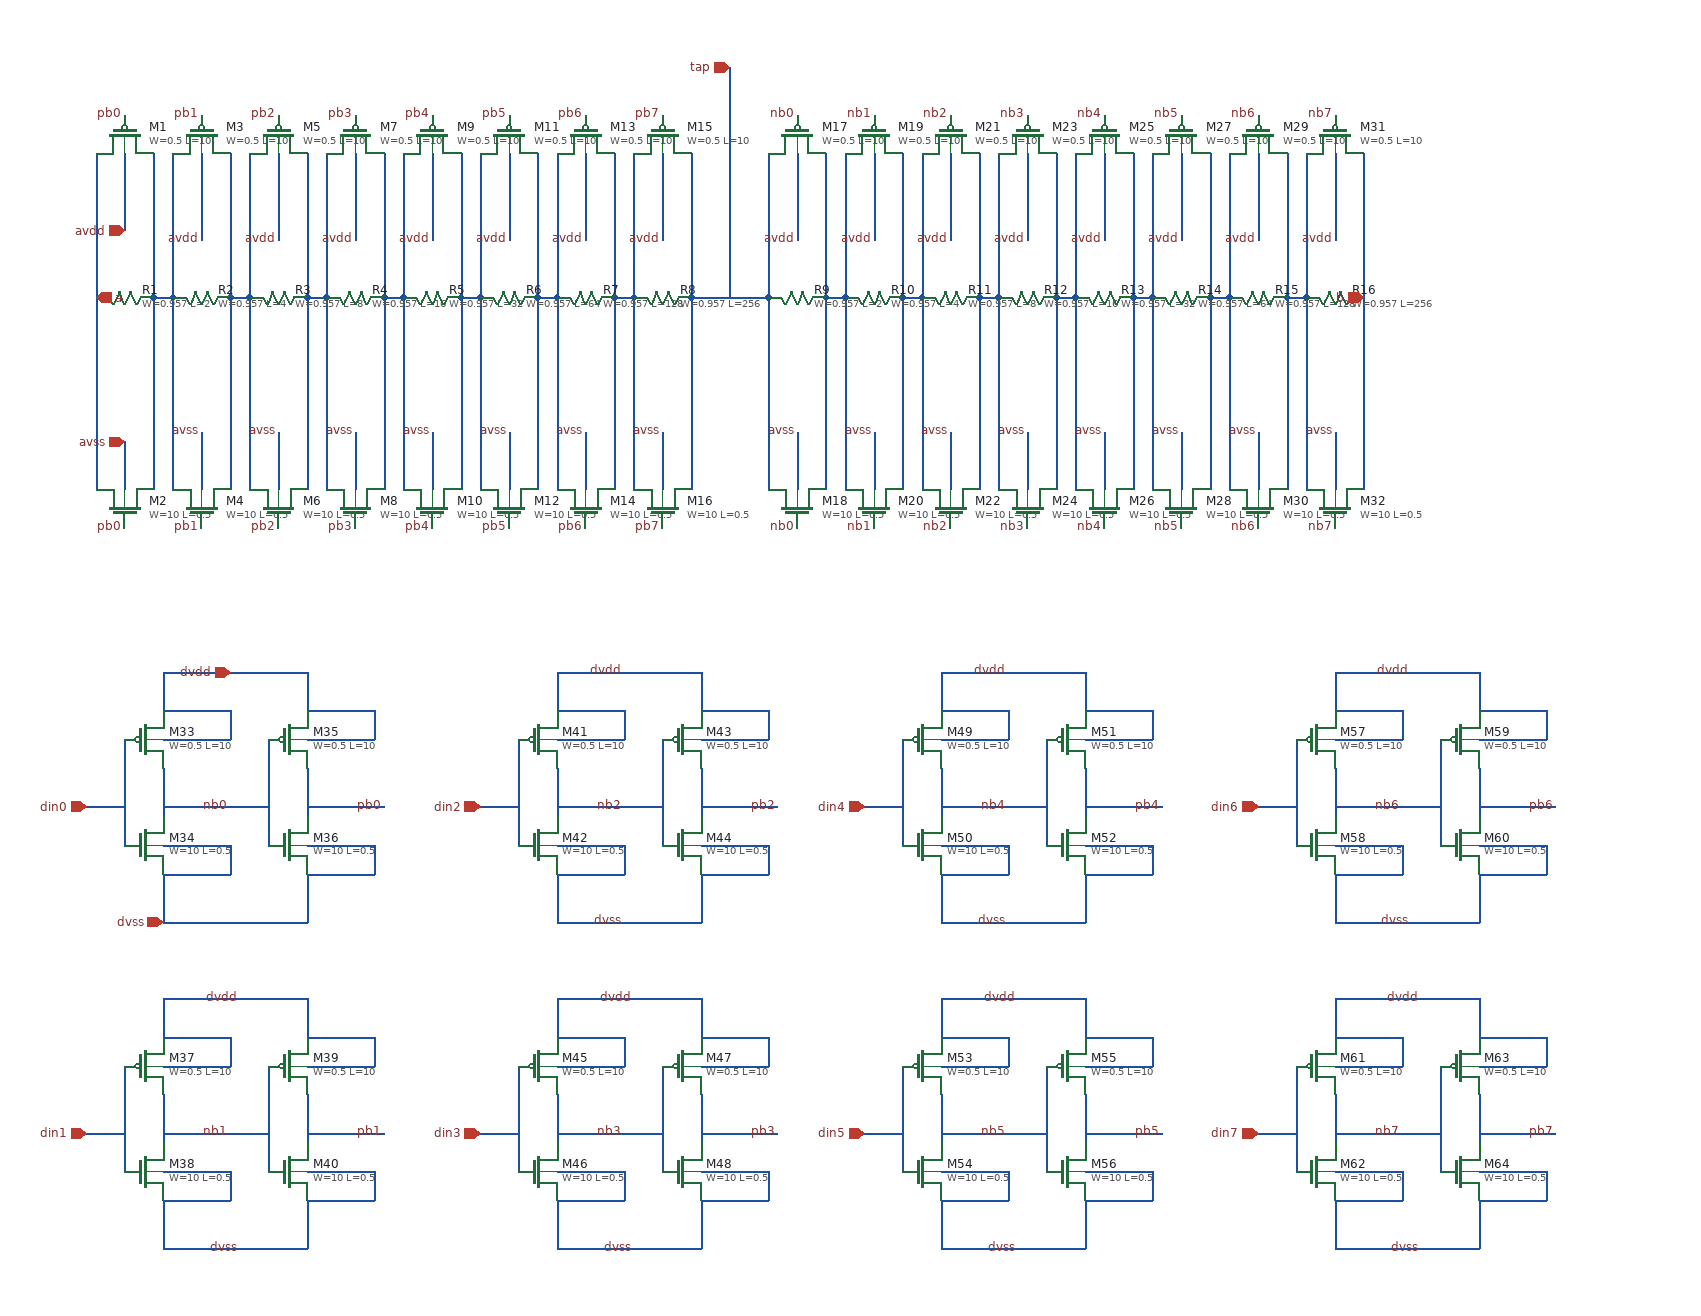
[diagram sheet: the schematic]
v {xschem version=3.4.5 file_version=1.2
}
G {}
K {}
V {}
S {}
E {}
N 70 -1160 70 -990 {
lab=a}
N 130 -1160 130 -990 {
lab=#net1}
N 150 -1160 150 -990 {
lab=#net1}
N 210 -1160 210 -990 {
lab=#net2}
N 230 -1160 230 -990 {
lab=#net2}
N 290 -1160 290 -990 {
lab=#net3}
N 310 -1160 310 -990 {
lab=#net3}
N 370 -1160 370 -990 {
lab=#net4}
N 390 -1160 390 -990 {
lab=#net4}
N 450 -1160 450 -990 {
lab=#net5}
N 470 -1160 470 -990 {
lab=#net5}
N 530 -1160 530 -990 {
lab=#net6}
N 550 -1160 550 -990 {
lab=#net6}
N 610 -1160 610 -990 {
lab=#net7}
N 630 -1160 630 -990 {
lab=#net7}
N 690 -1160 690 -990 {
lab=tap}
N 70 -990 70 -960 {
lab=a}
N 130 -990 130 -960 {
lab=#net1}
N 150 -990 150 -960 {
lab=#net1}
N 210 -990 210 -960 {
lab=#net2}
N 230 -990 230 -960 {
lab=#net2}
N 290 -990 290 -960 {
lab=#net3}
N 310 -990 310 -960 {
lab=#net3}
N 370 -990 370 -960 {
lab=#net4}
N 390 -990 390 -960 {
lab=#net4}
N 450 -990 450 -960 {
lab=#net5}
N 470 -990 470 -960 {
lab=#net5}
N 530 -990 530 -960 {
lab=#net6}
N 550 -990 550 -960 {
lab=#net6}
N 610 -990 610 -960 {
lab=#net7}
N 630 -990 630 -960 {
lab=#net7}
N 690 -990 690 -960 {
lab=tap}
N 70 -1310 70 -1160 {
lab=a}
N 130 -1310 130 -1160 {
lab=#net1}
N 150 -1310 150 -1160 {
lab=#net1}
N 210 -1310 210 -1160 {
lab=#net2}
N 230 -1310 230 -1160 {
lab=#net2}
N 290 -1310 290 -1160 {
lab=#net3}
N 310 -1310 310 -1160 {
lab=#net3}
N 370 -1310 370 -1160 {
lab=#net4}
N 390 -1310 390 -1160 {
lab=#net4}
N 450 -1310 450 -1160 {
lab=#net5}
N 470 -1310 470 -1160 {
lab=#net5}
N 530 -1310 530 -1160 {
lab=#net6}
N 550 -1310 550 -1160 {
lab=#net6}
N 610 -1310 610 -1160 {
lab=#net7}
N 630 -1310 630 -1160 {
lab=#net7}
N 690 -1310 690 -1160 {
lab=tap}
N 130 -1160 150 -1160 {
lab=#net1}
N 210 -1160 230 -1160 {
lab=#net2}
N 290 -1160 310 -1160 {
lab=#net3}
N 370 -1160 390 -1160 {
lab=#net4}
N 450 -1160 470 -1160 {
lab=#net5}
N 530 -1160 550 -1160 {
lab=#net6}
N 610 -1160 630 -1160 {
lab=#net7}
N 690 -1160 770 -1160 {
lab=tap}
N 770 -1160 770 -990 {
lab=tap}
N 830 -1160 830 -990 {
lab=#net8}
N 850 -1160 850 -990 {
lab=#net8}
N 910 -1160 910 -990 {
lab=#net9}
N 930 -1160 930 -990 {
lab=#net9}
N 990 -1160 990 -990 {
lab=#net10}
N 1010 -1160 1010 -990 {
lab=#net10}
N 1070 -1160 1070 -990 {
lab=#net11}
N 1090 -1160 1090 -990 {
lab=#net11}
N 1150 -1160 1150 -990 {
lab=#net12}
N 1170 -1160 1170 -990 {
lab=#net12}
N 1230 -1160 1230 -990 {
lab=#net13}
N 1250 -1160 1250 -990 {
lab=#net13}
N 1310 -1160 1310 -990 {
lab=#net14}
N 1330 -1160 1330 -990 {
lab=#net14}
N 1390 -1160 1390 -990 {
lab=b}
N 770 -990 770 -960 {
lab=tap}
N 830 -990 830 -960 {
lab=#net8}
N 850 -990 850 -960 {
lab=#net8}
N 910 -990 910 -960 {
lab=#net9}
N 930 -990 930 -960 {
lab=#net9}
N 990 -990 990 -960 {
lab=#net10}
N 1010 -990 1010 -960 {
lab=#net10}
N 1070 -990 1070 -960 {
lab=#net11}
N 1090 -990 1090 -960 {
lab=#net11}
N 1150 -990 1150 -960 {
lab=#net12}
N 1170 -990 1170 -960 {
lab=#net12}
N 1230 -990 1230 -960 {
lab=#net13}
N 1250 -990 1250 -960 {
lab=#net13}
N 1310 -990 1310 -960 {
lab=#net14}
N 1330 -990 1330 -960 {
lab=#net14}
N 1390 -990 1390 -960 {
lab=b}
N 770 -1310 770 -1160 {
lab=tap}
N 830 -1310 830 -1160 {
lab=#net8}
N 850 -1310 850 -1160 {
lab=#net8}
N 910 -1310 910 -1160 {
lab=#net9}
N 930 -1310 930 -1160 {
lab=#net9}
N 990 -1310 990 -1160 {
lab=#net10}
N 1010 -1310 1010 -1160 {
lab=#net10}
N 1070 -1310 1070 -1160 {
lab=#net11}
N 1090 -1310 1090 -1160 {
lab=#net11}
N 1150 -1310 1150 -1160 {
lab=#net12}
N 1170 -1310 1170 -1160 {
lab=#net12}
N 1230 -1310 1230 -1160 {
lab=#net13}
N 1250 -1310 1250 -1160 {
lab=#net13}
N 1310 -1310 1310 -1160 {
lab=#net14}
N 1330 -1310 1330 -1160 {
lab=#net14}
N 1390 -1310 1390 -1160 {
lab=b}
N 830 -1160 850 -1160 {
lab=#net8}
N 910 -1160 930 -1160 {
lab=#net9}
N 990 -1160 1010 -1160 {
lab=#net10}
N 1070 -1160 1090 -1160 {
lab=#net11}
N 1150 -1160 1170 -1160 {
lab=#net12}
N 1230 -1160 1250 -1160 {
lab=#net13}
N 1310 -1160 1330 -1160 {
lab=#net14}
N 140 -670 140 -620 {
lab=nb0}
N 140 -770 140 -730 {
lab=dvdd}
N 140 -560 140 -510 {
lab=dvss}
N 140 -700 210 -700 {
lab=dvdd}
N 210 -730 210 -700 {
lab=dvdd}
N 140 -730 210 -730 {
lab=dvdd}
N 140 -590 210 -590 {
lab=dvss}
N 210 -590 210 -560 {
lab=dvss}
N 140 -560 210 -560 {
lab=dvss}
N 100 -670 100 -590 {
lab=din0}
N 100 -700 100 -670 {
lab=din0}
N 290 -670 290 -620 {
lab=pb0}
N 290 -770 290 -730 {
lab=dvdd}
N 290 -560 290 -510 {
lab=dvss}
N 290 -700 360 -700 {
lab=dvdd}
N 360 -730 360 -700 {
lab=dvdd}
N 290 -730 360 -730 {
lab=dvdd}
N 290 -590 360 -590 {
lab=dvss}
N 360 -590 360 -560 {
lab=dvss}
N 290 -560 360 -560 {
lab=dvss}
N 250 -670 250 -590 {
lab=nb0}
N 250 -700 250 -670 {
lab=nb0}
N 140 -630 250 -630 {
lab=nb0}
N 140 -770 290 -770 {
lab=dvdd}
N 140 -510 290 -510 {
lab=dvss}
N 290 -630 370 -630 {
lab=pb0}
N 730 -1400 730 -1160 {
lab=tap}
N 60 -630 100 -630 {
lab=din0}
N 140 -330 140 -280 {
lab=nb1}
N 140 -430 140 -390 {
lab=#net15}
N 140 -220 140 -170 {
lab=#net16}
N 140 -360 210 -360 {
lab=#net15}
N 210 -390 210 -360 {
lab=#net15}
N 140 -390 210 -390 {
lab=#net15}
N 140 -250 210 -250 {
lab=#net16}
N 210 -250 210 -220 {
lab=#net16}
N 140 -220 210 -220 {
lab=#net16}
N 100 -330 100 -250 {
lab=din1}
N 100 -360 100 -330 {
lab=din1}
N 290 -330 290 -280 {
lab=pb1}
N 290 -430 290 -390 {
lab=#net15}
N 290 -220 290 -170 {
lab=#net16}
N 290 -360 360 -360 {
lab=#net15}
N 360 -390 360 -360 {
lab=#net15}
N 290 -390 360 -390 {
lab=#net15}
N 290 -250 360 -250 {
lab=#net16}
N 360 -250 360 -220 {
lab=#net16}
N 290 -220 360 -220 {
lab=#net16}
N 250 -330 250 -250 {
lab=nb1}
N 250 -360 250 -330 {
lab=nb1}
N 140 -290 250 -290 {
lab=nb1}
N 140 -430 290 -430 {
lab=#net15}
N 140 -170 290 -170 {
lab=#net16}
N 290 -290 370 -290 {
lab=pb1}
N 60 -290 100 -290 {
lab=din1}
N 550 -670 550 -620 {
lab=nb2}
N 550 -770 550 -730 {
lab=#net17}
N 550 -560 550 -510 {
lab=#net18}
N 550 -700 620 -700 {
lab=#net17}
N 620 -730 620 -700 {
lab=#net17}
N 550 -730 620 -730 {
lab=#net17}
N 550 -590 620 -590 {
lab=#net18}
N 620 -590 620 -560 {
lab=#net18}
N 550 -560 620 -560 {
lab=#net18}
N 510 -670 510 -590 {
lab=din2}
N 510 -700 510 -670 {
lab=din2}
N 700 -670 700 -620 {
lab=pb2}
N 700 -770 700 -730 {
lab=#net17}
N 700 -560 700 -510 {
lab=#net18}
N 700 -700 770 -700 {
lab=#net17}
N 770 -730 770 -700 {
lab=#net17}
N 700 -730 770 -730 {
lab=#net17}
N 700 -590 770 -590 {
lab=#net18}
N 770 -590 770 -560 {
lab=#net18}
N 700 -560 770 -560 {
lab=#net18}
N 660 -670 660 -590 {
lab=nb2}
N 660 -700 660 -670 {
lab=nb2}
N 550 -630 660 -630 {
lab=nb2}
N 550 -770 700 -770 {
lab=#net17}
N 550 -510 700 -510 {
lab=#net18}
N 700 -630 780 -630 {
lab=pb2}
N 470 -630 510 -630 {
lab=din2}
N 550 -330 550 -280 {
lab=nb3}
N 550 -430 550 -390 {
lab=#net19}
N 550 -220 550 -170 {
lab=#net20}
N 550 -360 620 -360 {
lab=#net19}
N 620 -390 620 -360 {
lab=#net19}
N 550 -390 620 -390 {
lab=#net19}
N 550 -250 620 -250 {
lab=#net20}
N 620 -250 620 -220 {
lab=#net20}
N 550 -220 620 -220 {
lab=#net20}
N 510 -330 510 -250 {
lab=din3}
N 510 -360 510 -330 {
lab=din3}
N 700 -330 700 -280 {
lab=pb3}
N 700 -430 700 -390 {
lab=#net19}
N 700 -220 700 -170 {
lab=#net20}
N 700 -360 770 -360 {
lab=#net19}
N 770 -390 770 -360 {
lab=#net19}
N 700 -390 770 -390 {
lab=#net19}
N 700 -250 770 -250 {
lab=#net20}
N 770 -250 770 -220 {
lab=#net20}
N 700 -220 770 -220 {
lab=#net20}
N 660 -330 660 -250 {
lab=nb3}
N 660 -360 660 -330 {
lab=nb3}
N 550 -290 660 -290 {
lab=nb3}
N 550 -430 700 -430 {
lab=#net19}
N 550 -170 700 -170 {
lab=#net20}
N 700 -290 780 -290 {
lab=pb3}
N 470 -290 510 -290 {
lab=din3}
N 950 -670 950 -620 {
lab=nb4}
N 950 -770 950 -730 {
lab=#net21}
N 950 -560 950 -510 {
lab=#net22}
N 950 -700 1020 -700 {
lab=#net21}
N 1020 -730 1020 -700 {
lab=#net21}
N 950 -730 1020 -730 {
lab=#net21}
N 950 -590 1020 -590 {
lab=#net22}
N 1020 -590 1020 -560 {
lab=#net22}
N 950 -560 1020 -560 {
lab=#net22}
N 910 -670 910 -590 {
lab=din4}
N 910 -700 910 -670 {
lab=din4}
N 1100 -670 1100 -620 {
lab=pb4}
N 1100 -770 1100 -730 {
lab=#net21}
N 1100 -560 1100 -510 {
lab=#net22}
N 1100 -700 1170 -700 {
lab=#net21}
N 1170 -730 1170 -700 {
lab=#net21}
N 1100 -730 1170 -730 {
lab=#net21}
N 1100 -590 1170 -590 {
lab=#net22}
N 1170 -590 1170 -560 {
lab=#net22}
N 1100 -560 1170 -560 {
lab=#net22}
N 1060 -670 1060 -590 {
lab=nb4}
N 1060 -700 1060 -670 {
lab=nb4}
N 950 -630 1060 -630 {
lab=nb4}
N 950 -770 1100 -770 {
lab=#net21}
N 950 -510 1100 -510 {
lab=#net22}
N 1100 -630 1180 -630 {
lab=pb4}
N 870 -630 910 -630 {
lab=din4}
N 950 -330 950 -280 {
lab=nb5}
N 950 -430 950 -390 {
lab=#net23}
N 950 -220 950 -170 {
lab=#net24}
N 950 -360 1020 -360 {
lab=#net23}
N 1020 -390 1020 -360 {
lab=#net23}
N 950 -390 1020 -390 {
lab=#net23}
N 950 -250 1020 -250 {
lab=#net24}
N 1020 -250 1020 -220 {
lab=#net24}
N 950 -220 1020 -220 {
lab=#net24}
N 910 -330 910 -250 {
lab=din5}
N 910 -360 910 -330 {
lab=din5}
N 1100 -330 1100 -280 {
lab=pb5}
N 1100 -430 1100 -390 {
lab=#net23}
N 1100 -220 1100 -170 {
lab=#net24}
N 1100 -360 1170 -360 {
lab=#net23}
N 1170 -390 1170 -360 {
lab=#net23}
N 1100 -390 1170 -390 {
lab=#net23}
N 1100 -250 1170 -250 {
lab=#net24}
N 1170 -250 1170 -220 {
lab=#net24}
N 1100 -220 1170 -220 {
lab=#net24}
N 1060 -330 1060 -250 {
lab=nb5}
N 1060 -360 1060 -330 {
lab=nb5}
N 950 -290 1060 -290 {
lab=nb5}
N 950 -430 1100 -430 {
lab=#net23}
N 950 -170 1100 -170 {
lab=#net24}
N 1100 -290 1180 -290 {
lab=pb5}
N 870 -290 910 -290 {
lab=din5}
N 1360 -670 1360 -620 {
lab=nb6}
N 1360 -770 1360 -730 {
lab=#net25}
N 1360 -560 1360 -510 {
lab=#net26}
N 1360 -700 1430 -700 {
lab=#net25}
N 1430 -730 1430 -700 {
lab=#net25}
N 1360 -730 1430 -730 {
lab=#net25}
N 1360 -590 1430 -590 {
lab=#net26}
N 1430 -590 1430 -560 {
lab=#net26}
N 1360 -560 1430 -560 {
lab=#net26}
N 1320 -670 1320 -590 {
lab=din6}
N 1320 -700 1320 -670 {
lab=din6}
N 1510 -670 1510 -620 {
lab=pb6}
N 1510 -770 1510 -730 {
lab=#net25}
N 1510 -560 1510 -510 {
lab=#net26}
N 1510 -700 1580 -700 {
lab=#net25}
N 1580 -730 1580 -700 {
lab=#net25}
N 1510 -730 1580 -730 {
lab=#net25}
N 1510 -590 1580 -590 {
lab=#net26}
N 1580 -590 1580 -560 {
lab=#net26}
N 1510 -560 1580 -560 {
lab=#net26}
N 1470 -670 1470 -590 {
lab=nb6}
N 1470 -700 1470 -670 {
lab=nb6}
N 1360 -630 1470 -630 {
lab=nb6}
N 1360 -770 1510 -770 {
lab=#net25}
N 1360 -510 1510 -510 {
lab=#net26}
N 1510 -630 1590 -630 {
lab=pb6}
N 1280 -630 1320 -630 {
lab=din6}
N 1360 -330 1360 -280 {
lab=nb7}
N 1360 -430 1360 -390 {
lab=#net27}
N 1360 -220 1360 -170 {
lab=#net28}
N 1360 -360 1430 -360 {
lab=#net27}
N 1430 -390 1430 -360 {
lab=#net27}
N 1360 -390 1430 -390 {
lab=#net27}
N 1360 -250 1430 -250 {
lab=#net28}
N 1430 -250 1430 -220 {
lab=#net28}
N 1360 -220 1430 -220 {
lab=#net28}
N 1320 -330 1320 -250 {
lab=din7}
N 1320 -360 1320 -330 {
lab=din7}
N 1510 -330 1510 -280 {
lab=pb7}
N 1510 -430 1510 -390 {
lab=#net27}
N 1510 -220 1510 -170 {
lab=#net28}
N 1510 -360 1580 -360 {
lab=#net27}
N 1580 -390 1580 -360 {
lab=#net27}
N 1510 -390 1580 -390 {
lab=#net27}
N 1510 -250 1580 -250 {
lab=#net28}
N 1580 -250 1580 -220 {
lab=#net28}
N 1510 -220 1580 -220 {
lab=#net28}
N 1470 -330 1470 -250 {
lab=nb7}
N 1470 -360 1470 -330 {
lab=nb7}
N 1360 -290 1470 -290 {
lab=nb7}
N 1360 -430 1510 -430 {
lab=#net27}
N 1360 -170 1510 -170 {
lab=#net28}
N 1510 -290 1590 -290 {
lab=pb7}
N 1280 -290 1320 -290 {
lab=din7}
N 180 -1020 180 -960 {}
N 260 -1020 260 -960 {}
N 340 -1020 340 -960 {}
N 420 -1020 420 -960 {}
N 500 -1020 500 -960 {}
N 580 -1020 580 -960 {}
N 660 -1020 660 -960 {}
N 800 -1020 800 -960 {}
N 880 -1020 880 -960 {}
N 960 -1020 960 -960 {}
N 1040 -1020 1040 -960 {}
N 1120 -1020 1120 -960 {}
N 1200 -1020 1200 -960 {}
N 1280 -1020 1280 -960 {}
N 1360 -1020 1360 -960 {}
N 180 -1310 180 -1220 {}
N 260 -1310 260 -1220 {}
N 340 -1310 340 -1220 {}
N 420 -1310 420 -1220 {}
N 500 -1310 500 -1220 {}
N 580 -1310 580 -1220 {}
N 660 -1310 660 -1220 {}
N 800 -1310 800 -1220 {}
N 880 -1310 880 -1220 {}
N 960 -1310 960 -1220 {}
N 1040 -1310 1040 -1220 {}
N 1120 -1310 1120 -1220 {}
N 1200 -1310 1200 -1220 {}
N 1280 -1310 1280 -1220 {}
N 1360 -1310 1360 -1220 {}
N 100 -1010 100 -960 {}
N 100 -1310 100 -1230 {}
C {sky130_fd_pr/pfet_g5v0d10v5.sym} 100 -1330 1 0 {name=M1
L=10
W=0.5
nf=1
mult=1
ad="'int((nf+1)/2) * W/nf * 0.29'" 
pd="'2*int((nf+1)/2) * (W/nf + 0.29)'"
as="'int((nf+2)/2) * W/nf * 0.29'" 
ps="'2*int((nf+2)/2) * (W/nf + 0.29)'"
nrd="'0.29 / W'" nrs="'0.29 / W'"
sa=0 sb=0 sd=0
model=pfet_g5v0d10v5
spiceprefix=X
}
C {sky130_fd_pr/nfet_g5v0d10v5.sym} 100 -940 3 0 {name=M2
L=0.5
W=10
nf=1
mult=1
ad="'int((nf+1)/2) * W/nf * 0.29'" 
pd="'2*int((nf+1)/2) * (W/nf + 0.29)'"
as="'int((nf+2)/2) * W/nf * 0.29'" 
ps="'2*int((nf+2)/2) * (W/nf + 0.29)'"
nrd="'0.29 / W'" nrs="'0.29 / W'"
sa=0 sb=0 sd=0
model=nfet_g5v0d10v5
spiceprefix=X
}
C {sky130_fd_pr/pfet_g5v0d10v5.sym} 180 -1330 1 0 {name=M3
L=10
W=0.5
nf=1
mult=1
ad="'int((nf+1)/2) * W/nf * 0.29'" 
pd="'2*int((nf+1)/2) * (W/nf + 0.29)'"
as="'int((nf+2)/2) * W/nf * 0.29'" 
ps="'2*int((nf+2)/2) * (W/nf + 0.29)'"
nrd="'0.29 / W'" nrs="'0.29 / W'"
sa=0 sb=0 sd=0
model=pfet_g5v0d10v5
spiceprefix=X
}
C {sky130_fd_pr/nfet_g5v0d10v5.sym} 180 -940 3 0 {name=M4
L=0.5
W=10
nf=1
mult=1
ad="'int((nf+1)/2) * W/nf * 0.29'" 
pd="'2*int((nf+1)/2) * (W/nf + 0.29)'"
as="'int((nf+2)/2) * W/nf * 0.29'" 
ps="'2*int((nf+2)/2) * (W/nf + 0.29)'"
nrd="'0.29 / W'" nrs="'0.29 / W'"
sa=0 sb=0 sd=0
model=nfet_g5v0d10v5
spiceprefix=X
}
C {sky130_fd_pr/pfet_g5v0d10v5.sym} 260 -1330 1 0 {name=M5
L=10
W=0.5
nf=1
mult=1
ad="'int((nf+1)/2) * W/nf * 0.29'" 
pd="'2*int((nf+1)/2) * (W/nf + 0.29)'"
as="'int((nf+2)/2) * W/nf * 0.29'" 
ps="'2*int((nf+2)/2) * (W/nf + 0.29)'"
nrd="'0.29 / W'" nrs="'0.29 / W'"
sa=0 sb=0 sd=0
model=pfet_g5v0d10v5
spiceprefix=X
}
C {sky130_fd_pr/nfet_g5v0d10v5.sym} 260 -940 3 0 {name=M6
L=0.5
W=10
nf=1
mult=1
ad="'int((nf+1)/2) * W/nf * 0.29'" 
pd="'2*int((nf+1)/2) * (W/nf + 0.29)'"
as="'int((nf+2)/2) * W/nf * 0.29'" 
ps="'2*int((nf+2)/2) * (W/nf + 0.29)'"
nrd="'0.29 / W'" nrs="'0.29 / W'"
sa=0 sb=0 sd=0
model=nfet_g5v0d10v5
spiceprefix=X
}
C {sky130_fd_pr/pfet_g5v0d10v5.sym} 340 -1330 1 0 {name=M7
L=10
W=0.5
nf=1
mult=1
ad="'int((nf+1)/2) * W/nf * 0.29'" 
pd="'2*int((nf+1)/2) * (W/nf + 0.29)'"
as="'int((nf+2)/2) * W/nf * 0.29'" 
ps="'2*int((nf+2)/2) * (W/nf + 0.29)'"
nrd="'0.29 / W'" nrs="'0.29 / W'"
sa=0 sb=0 sd=0
model=pfet_g5v0d10v5
spiceprefix=X
}
C {sky130_fd_pr/nfet_g5v0d10v5.sym} 340 -940 3 0 {name=M8
L=0.5
W=10
nf=1
mult=1
ad="'int((nf+1)/2) * W/nf * 0.29'" 
pd="'2*int((nf+1)/2) * (W/nf + 0.29)'"
as="'int((nf+2)/2) * W/nf * 0.29'" 
ps="'2*int((nf+2)/2) * (W/nf + 0.29)'"
nrd="'0.29 / W'" nrs="'0.29 / W'"
sa=0 sb=0 sd=0
model=nfet_g5v0d10v5
spiceprefix=X
}
C {sky130_fd_pr/pfet_g5v0d10v5.sym} 420 -1330 1 0 {name=M9
L=10
W=0.5
nf=1
mult=1
ad="'int((nf+1)/2) * W/nf * 0.29'" 
pd="'2*int((nf+1)/2) * (W/nf + 0.29)'"
as="'int((nf+2)/2) * W/nf * 0.29'" 
ps="'2*int((nf+2)/2) * (W/nf + 0.29)'"
nrd="'0.29 / W'" nrs="'0.29 / W'"
sa=0 sb=0 sd=0
model=pfet_g5v0d10v5
spiceprefix=X
}
C {sky130_fd_pr/nfet_g5v0d10v5.sym} 420 -940 3 0 {name=M10
L=0.5
W=10
nf=1
mult=1
ad="'int((nf+1)/2) * W/nf * 0.29'" 
pd="'2*int((nf+1)/2) * (W/nf + 0.29)'"
as="'int((nf+2)/2) * W/nf * 0.29'" 
ps="'2*int((nf+2)/2) * (W/nf + 0.29)'"
nrd="'0.29 / W'" nrs="'0.29 / W'"
sa=0 sb=0 sd=0
model=nfet_g5v0d10v5
spiceprefix=X
}
C {sky130_fd_pr/pfet_g5v0d10v5.sym} 500 -1330 1 0 {name=M11
L=10
W=0.5
nf=1
mult=1
ad="'int((nf+1)/2) * W/nf * 0.29'" 
pd="'2*int((nf+1)/2) * (W/nf + 0.29)'"
as="'int((nf+2)/2) * W/nf * 0.29'" 
ps="'2*int((nf+2)/2) * (W/nf + 0.29)'"
nrd="'0.29 / W'" nrs="'0.29 / W'"
sa=0 sb=0 sd=0
model=pfet_g5v0d10v5
spiceprefix=X
}
C {sky130_fd_pr/nfet_g5v0d10v5.sym} 500 -940 3 0 {name=M12
L=0.5
W=10
nf=1
mult=1
ad="'int((nf+1)/2) * W/nf * 0.29'" 
pd="'2*int((nf+1)/2) * (W/nf + 0.29)'"
as="'int((nf+2)/2) * W/nf * 0.29'" 
ps="'2*int((nf+2)/2) * (W/nf + 0.29)'"
nrd="'0.29 / W'" nrs="'0.29 / W'"
sa=0 sb=0 sd=0
model=nfet_g5v0d10v5
spiceprefix=X
}
C {sky130_fd_pr/pfet_g5v0d10v5.sym} 580 -1330 1 0 {name=M13
L=10
W=0.5
nf=1
mult=1
ad="'int((nf+1)/2) * W/nf * 0.29'" 
pd="'2*int((nf+1)/2) * (W/nf + 0.29)'"
as="'int((nf+2)/2) * W/nf * 0.29'" 
ps="'2*int((nf+2)/2) * (W/nf + 0.29)'"
nrd="'0.29 / W'" nrs="'0.29 / W'"
sa=0 sb=0 sd=0
model=pfet_g5v0d10v5
spiceprefix=X
}
C {sky130_fd_pr/nfet_g5v0d10v5.sym} 580 -940 3 0 {name=M14
L=0.5
W=10
nf=1
mult=1
ad="'int((nf+1)/2) * W/nf * 0.29'" 
pd="'2*int((nf+1)/2) * (W/nf + 0.29)'"
as="'int((nf+2)/2) * W/nf * 0.29'" 
ps="'2*int((nf+2)/2) * (W/nf + 0.29)'"
nrd="'0.29 / W'" nrs="'0.29 / W'"
sa=0 sb=0 sd=0
model=nfet_g5v0d10v5
spiceprefix=X
}
C {sky130_fd_pr/pfet_g5v0d10v5.sym} 660 -1330 1 0 {name=M15
L=10
W=0.5
nf=1
mult=1
ad="'int((nf+1)/2) * W/nf * 0.29'" 
pd="'2*int((nf+1)/2) * (W/nf + 0.29)'"
as="'int((nf+2)/2) * W/nf * 0.29'" 
ps="'2*int((nf+2)/2) * (W/nf + 0.29)'"
nrd="'0.29 / W'" nrs="'0.29 / W'"
sa=0 sb=0 sd=0
model=pfet_g5v0d10v5
spiceprefix=X
}
C {sky130_fd_pr/nfet_g5v0d10v5.sym} 660 -940 3 0 {name=M16
L=0.5
W=10
nf=1
mult=1
ad="'int((nf+1)/2) * W/nf * 0.29'" 
pd="'2*int((nf+1)/2) * (W/nf + 0.29)'"
as="'int((nf+2)/2) * W/nf * 0.29'" 
ps="'2*int((nf+2)/2) * (W/nf + 0.29)'"
nrd="'0.29 / W'" nrs="'0.29 / W'"
sa=0 sb=0 sd=0
model=nfet_g5v0d10v5
spiceprefix=X
}
C {sky130_fd_pr/res_generic_po.sym} 100 -1160 1 0 {name=R1
W=0.957
L=2
model=res_generic_po
mult=1}
C {sky130_fd_pr/res_generic_po.sym} 180 -1160 1 0 {name=R2
W=0.957
L=4
model=res_generic_po
mult=1}
C {sky130_fd_pr/res_generic_po.sym} 260 -1160 1 0 {name=R3
W=0.957
L=8
model=res_generic_po
mult=1}
C {sky130_fd_pr/res_generic_po.sym} 340 -1160 1 0 {name=R4
W=0.957
L=16
model=res_generic_po
mult=1}
C {sky130_fd_pr/res_generic_po.sym} 420 -1160 1 0 {name=R5
W=0.957
L=32
model=res_generic_po
mult=1}
C {sky130_fd_pr/res_generic_po.sym} 500 -1160 1 0 {name=R6
W=0.957
L=64
model=res_generic_po
mult=1}
C {sky130_fd_pr/res_generic_po.sym} 580 -1160 1 0 {name=R7
W=0.957
L=128
model=res_generic_po
mult=1}
C {sky130_fd_pr/res_generic_po.sym} 660 -1160 1 0 {name=R8
W=0.957
L=256
model=res_generic_po
mult=1}
C {sky130_fd_pr/pfet_g5v0d10v5.sym} 800 -1330 1 0 {name=M17
L=10
W=0.5
nf=1
mult=1
ad="'int((nf+1)/2) * W/nf * 0.29'" 
pd="'2*int((nf+1)/2) * (W/nf + 0.29)'"
as="'int((nf+2)/2) * W/nf * 0.29'" 
ps="'2*int((nf+2)/2) * (W/nf + 0.29)'"
nrd="'0.29 / W'" nrs="'0.29 / W'"
sa=0 sb=0 sd=0
model=pfet_g5v0d10v5
spiceprefix=X
}
C {sky130_fd_pr/nfet_g5v0d10v5.sym} 800 -940 3 0 {name=M18
L=0.5
W=10
nf=1
mult=1
ad="'int((nf+1)/2) * W/nf * 0.29'" 
pd="'2*int((nf+1)/2) * (W/nf + 0.29)'"
as="'int((nf+2)/2) * W/nf * 0.29'" 
ps="'2*int((nf+2)/2) * (W/nf + 0.29)'"
nrd="'0.29 / W'" nrs="'0.29 / W'"
sa=0 sb=0 sd=0
model=nfet_g5v0d10v5
spiceprefix=X
}
C {sky130_fd_pr/pfet_g5v0d10v5.sym} 880 -1330 1 0 {name=M19
L=10
W=0.5
nf=1
mult=1
ad="'int((nf+1)/2) * W/nf * 0.29'" 
pd="'2*int((nf+1)/2) * (W/nf + 0.29)'"
as="'int((nf+2)/2) * W/nf * 0.29'" 
ps="'2*int((nf+2)/2) * (W/nf + 0.29)'"
nrd="'0.29 / W'" nrs="'0.29 / W'"
sa=0 sb=0 sd=0
model=pfet_g5v0d10v5
spiceprefix=X
}
C {sky130_fd_pr/nfet_g5v0d10v5.sym} 880 -940 3 0 {name=M20
L=0.5
W=10
nf=1
mult=1
ad="'int((nf+1)/2) * W/nf * 0.29'" 
pd="'2*int((nf+1)/2) * (W/nf + 0.29)'"
as="'int((nf+2)/2) * W/nf * 0.29'" 
ps="'2*int((nf+2)/2) * (W/nf + 0.29)'"
nrd="'0.29 / W'" nrs="'0.29 / W'"
sa=0 sb=0 sd=0
model=nfet_g5v0d10v5
spiceprefix=X
}
C {sky130_fd_pr/pfet_g5v0d10v5.sym} 960 -1330 1 0 {name=M21
L=10
W=0.5
nf=1
mult=1
ad="'int((nf+1)/2) * W/nf * 0.29'" 
pd="'2*int((nf+1)/2) * (W/nf + 0.29)'"
as="'int((nf+2)/2) * W/nf * 0.29'" 
ps="'2*int((nf+2)/2) * (W/nf + 0.29)'"
nrd="'0.29 / W'" nrs="'0.29 / W'"
sa=0 sb=0 sd=0
model=pfet_g5v0d10v5
spiceprefix=X
}
C {sky130_fd_pr/nfet_g5v0d10v5.sym} 960 -940 3 0 {name=M22
L=0.5
W=10
nf=1
mult=1
ad="'int((nf+1)/2) * W/nf * 0.29'" 
pd="'2*int((nf+1)/2) * (W/nf + 0.29)'"
as="'int((nf+2)/2) * W/nf * 0.29'" 
ps="'2*int((nf+2)/2) * (W/nf + 0.29)'"
nrd="'0.29 / W'" nrs="'0.29 / W'"
sa=0 sb=0 sd=0
model=nfet_g5v0d10v5
spiceprefix=X
}
C {sky130_fd_pr/pfet_g5v0d10v5.sym} 1040 -1330 1 0 {name=M23
L=10
W=0.5
nf=1
mult=1
ad="'int((nf+1)/2) * W/nf * 0.29'" 
pd="'2*int((nf+1)/2) * (W/nf + 0.29)'"
as="'int((nf+2)/2) * W/nf * 0.29'" 
ps="'2*int((nf+2)/2) * (W/nf + 0.29)'"
nrd="'0.29 / W'" nrs="'0.29 / W'"
sa=0 sb=0 sd=0
model=pfet_g5v0d10v5
spiceprefix=X
}
C {sky130_fd_pr/nfet_g5v0d10v5.sym} 1040 -940 3 0 {name=M24
L=0.5
W=10
nf=1
mult=1
ad="'int((nf+1)/2) * W/nf * 0.29'" 
pd="'2*int((nf+1)/2) * (W/nf + 0.29)'"
as="'int((nf+2)/2) * W/nf * 0.29'" 
ps="'2*int((nf+2)/2) * (W/nf + 0.29)'"
nrd="'0.29 / W'" nrs="'0.29 / W'"
sa=0 sb=0 sd=0
model=nfet_g5v0d10v5
spiceprefix=X
}
C {sky130_fd_pr/pfet_g5v0d10v5.sym} 1120 -1330 1 0 {name=M25
L=10
W=0.5
nf=1
mult=1
ad="'int((nf+1)/2) * W/nf * 0.29'" 
pd="'2*int((nf+1)/2) * (W/nf + 0.29)'"
as="'int((nf+2)/2) * W/nf * 0.29'" 
ps="'2*int((nf+2)/2) * (W/nf + 0.29)'"
nrd="'0.29 / W'" nrs="'0.29 / W'"
sa=0 sb=0 sd=0
model=pfet_g5v0d10v5
spiceprefix=X
}
C {sky130_fd_pr/nfet_g5v0d10v5.sym} 1120 -940 3 0 {name=M26
L=0.5
W=10
nf=1
mult=1
ad="'int((nf+1)/2) * W/nf * 0.29'" 
pd="'2*int((nf+1)/2) * (W/nf + 0.29)'"
as="'int((nf+2)/2) * W/nf * 0.29'" 
ps="'2*int((nf+2)/2) * (W/nf + 0.29)'"
nrd="'0.29 / W'" nrs="'0.29 / W'"
sa=0 sb=0 sd=0
model=nfet_g5v0d10v5
spiceprefix=X
}
C {sky130_fd_pr/pfet_g5v0d10v5.sym} 1200 -1330 1 0 {name=M27
L=10
W=0.5
nf=1
mult=1
ad="'int((nf+1)/2) * W/nf * 0.29'" 
pd="'2*int((nf+1)/2) * (W/nf + 0.29)'"
as="'int((nf+2)/2) * W/nf * 0.29'" 
ps="'2*int((nf+2)/2) * (W/nf + 0.29)'"
nrd="'0.29 / W'" nrs="'0.29 / W'"
sa=0 sb=0 sd=0
model=pfet_g5v0d10v5
spiceprefix=X
}
C {sky130_fd_pr/nfet_g5v0d10v5.sym} 1200 -940 3 0 {name=M28
L=0.5
W=10
nf=1
mult=1
ad="'int((nf+1)/2) * W/nf * 0.29'" 
pd="'2*int((nf+1)/2) * (W/nf + 0.29)'"
as="'int((nf+2)/2) * W/nf * 0.29'" 
ps="'2*int((nf+2)/2) * (W/nf + 0.29)'"
nrd="'0.29 / W'" nrs="'0.29 / W'"
sa=0 sb=0 sd=0
model=nfet_g5v0d10v5
spiceprefix=X
}
C {sky130_fd_pr/pfet_g5v0d10v5.sym} 1280 -1330 1 0 {name=M29
L=10
W=0.5
nf=1
mult=1
ad="'int((nf+1)/2) * W/nf * 0.29'" 
pd="'2*int((nf+1)/2) * (W/nf + 0.29)'"
as="'int((nf+2)/2) * W/nf * 0.29'" 
ps="'2*int((nf+2)/2) * (W/nf + 0.29)'"
nrd="'0.29 / W'" nrs="'0.29 / W'"
sa=0 sb=0 sd=0
model=pfet_g5v0d10v5
spiceprefix=X
}
C {sky130_fd_pr/nfet_g5v0d10v5.sym} 1280 -940 3 0 {name=M30
L=0.5
W=10
nf=1
mult=1
ad="'int((nf+1)/2) * W/nf * 0.29'" 
pd="'2*int((nf+1)/2) * (W/nf + 0.29)'"
as="'int((nf+2)/2) * W/nf * 0.29'" 
ps="'2*int((nf+2)/2) * (W/nf + 0.29)'"
nrd="'0.29 / W'" nrs="'0.29 / W'"
sa=0 sb=0 sd=0
model=nfet_g5v0d10v5
spiceprefix=X
}
C {sky130_fd_pr/pfet_g5v0d10v5.sym} 1360 -1330 1 0 {name=M31
L=10
W=0.5
nf=1
mult=1
ad="'int((nf+1)/2) * W/nf * 0.29'" 
pd="'2*int((nf+1)/2) * (W/nf + 0.29)'"
as="'int((nf+2)/2) * W/nf * 0.29'" 
ps="'2*int((nf+2)/2) * (W/nf + 0.29)'"
nrd="'0.29 / W'" nrs="'0.29 / W'"
sa=0 sb=0 sd=0
model=pfet_g5v0d10v5
spiceprefix=X
}
C {sky130_fd_pr/nfet_g5v0d10v5.sym} 1360 -940 3 0 {name=M32
L=0.5
W=10
nf=1
mult=1
ad="'int((nf+1)/2) * W/nf * 0.29'" 
pd="'2*int((nf+1)/2) * (W/nf + 0.29)'"
as="'int((nf+2)/2) * W/nf * 0.29'" 
ps="'2*int((nf+2)/2) * (W/nf + 0.29)'"
nrd="'0.29 / W'" nrs="'0.29 / W'"
sa=0 sb=0 sd=0
model=nfet_g5v0d10v5
spiceprefix=X
}
C {sky130_fd_pr/res_generic_po.sym} 800 -1160 1 0 {name=R9
W=0.957
L=2
model=res_generic_po
mult=1}
C {sky130_fd_pr/res_generic_po.sym} 880 -1160 1 0 {name=R10
W=0.957
L=4
model=res_generic_po
mult=1}
C {sky130_fd_pr/res_generic_po.sym} 960 -1160 1 0 {name=R11
W=0.957
L=8
model=res_generic_po
mult=1}
C {sky130_fd_pr/res_generic_po.sym} 1040 -1160 1 0 {name=R12
W=0.957
L=16
model=res_generic_po
mult=1}
C {sky130_fd_pr/res_generic_po.sym} 1120 -1160 1 0 {name=R13
W=0.957
L=32
model=res_generic_po
mult=1}
C {sky130_fd_pr/res_generic_po.sym} 1200 -1160 1 0 {name=R14
W=0.957
L=64
model=res_generic_po
mult=1}
C {sky130_fd_pr/res_generic_po.sym} 1280 -1160 1 0 {name=R15
W=0.957
L=128
model=res_generic_po
mult=1}
C {sky130_fd_pr/res_generic_po.sym} 1360 -1160 1 0 {name=R16
W=0.957
L=256
model=res_generic_po
mult=1}
C {sky130_fd_pr/pfet_g5v0d10v5.sym} 120 -700 0 0 {name=M33
L=10
W=0.5
nf=1
mult=1
ad="'int((nf+1)/2) * W/nf * 0.29'" 
pd="'2*int((nf+1)/2) * (W/nf + 0.29)'"
as="'int((nf+2)/2) * W/nf * 0.29'" 
ps="'2*int((nf+2)/2) * (W/nf + 0.29)'"
nrd="'0.29 / W'" nrs="'0.29 / W'"
sa=0 sb=0 sd=0
model=pfet_g5v0d10v5
spiceprefix=X
}
C {sky130_fd_pr/nfet_g5v0d10v5.sym} 120 -590 0 0 {name=M34
L=0.5
W=10
nf=1
mult=1
ad="'int((nf+1)/2) * W/nf * 0.29'" 
pd="'2*int((nf+1)/2) * (W/nf + 0.29)'"
as="'int((nf+2)/2) * W/nf * 0.29'" 
ps="'2*int((nf+2)/2) * (W/nf + 0.29)'"
nrd="'0.29 / W'" nrs="'0.29 / W'"
sa=0 sb=0 sd=0
model=nfet_g5v0d10v5
spiceprefix=X
}
C {sky130_fd_pr/pfet_g5v0d10v5.sym} 270 -700 0 0 {name=M35
L=10
W=0.5
nf=1
mult=1
ad="'int((nf+1)/2) * W/nf * 0.29'" 
pd="'2*int((nf+1)/2) * (W/nf + 0.29)'"
as="'int((nf+2)/2) * W/nf * 0.29'" 
ps="'2*int((nf+2)/2) * (W/nf + 0.29)'"
nrd="'0.29 / W'" nrs="'0.29 / W'"
sa=0 sb=0 sd=0
model=pfet_g5v0d10v5
spiceprefix=X
}
C {sky130_fd_pr/nfet_g5v0d10v5.sym} 270 -590 0 0 {name=M36
L=0.5
W=10
nf=1
mult=1
ad="'int((nf+1)/2) * W/nf * 0.29'" 
pd="'2*int((nf+1)/2) * (W/nf + 0.29)'"
as="'int((nf+2)/2) * W/nf * 0.29'" 
ps="'2*int((nf+2)/2) * (W/nf + 0.29)'"
nrd="'0.29 / W'" nrs="'0.29 / W'"
sa=0 sb=0 sd=0
model=nfet_g5v0d10v5
spiceprefix=X
}
C {devices/lab_wire.sym} 210 -630 0 0 {name=p2 sig_type=std_logic lab=nb0}
C {devices/lab_wire.sym} 370 -630 0 0 {name=p3 sig_type=std_logic lab=pb0}
C {devices/ipin.sym} 60 -630 0 0 {name=p4 lab=din0}
C {sky130_fd_pr/pfet_g5v0d10v5.sym} 120 -360 0 0 {name=M37
L=10
W=0.5
nf=1
mult=1
ad="'int((nf+1)/2) * W/nf * 0.29'" 
pd="'2*int((nf+1)/2) * (W/nf + 0.29)'"
as="'int((nf+2)/2) * W/nf * 0.29'" 
ps="'2*int((nf+2)/2) * (W/nf + 0.29)'"
nrd="'0.29 / W'" nrs="'0.29 / W'"
sa=0 sb=0 sd=0
model=pfet_g5v0d10v5
spiceprefix=X
}
C {sky130_fd_pr/nfet_g5v0d10v5.sym} 120 -250 0 0 {name=M38
L=0.5
W=10
nf=1
mult=1
ad="'int((nf+1)/2) * W/nf * 0.29'" 
pd="'2*int((nf+1)/2) * (W/nf + 0.29)'"
as="'int((nf+2)/2) * W/nf * 0.29'" 
ps="'2*int((nf+2)/2) * (W/nf + 0.29)'"
nrd="'0.29 / W'" nrs="'0.29 / W'"
sa=0 sb=0 sd=0
model=nfet_g5v0d10v5
spiceprefix=X
}
C {sky130_fd_pr/pfet_g5v0d10v5.sym} 270 -360 0 0 {name=M39
L=10
W=0.5
nf=1
mult=1
ad="'int((nf+1)/2) * W/nf * 0.29'" 
pd="'2*int((nf+1)/2) * (W/nf + 0.29)'"
as="'int((nf+2)/2) * W/nf * 0.29'" 
ps="'2*int((nf+2)/2) * (W/nf + 0.29)'"
nrd="'0.29 / W'" nrs="'0.29 / W'"
sa=0 sb=0 sd=0
model=pfet_g5v0d10v5
spiceprefix=X
}
C {sky130_fd_pr/nfet_g5v0d10v5.sym} 270 -250 0 0 {name=M40
L=0.5
W=10
nf=1
mult=1
ad="'int((nf+1)/2) * W/nf * 0.29'" 
pd="'2*int((nf+1)/2) * (W/nf + 0.29)'"
as="'int((nf+2)/2) * W/nf * 0.29'" 
ps="'2*int((nf+2)/2) * (W/nf + 0.29)'"
nrd="'0.29 / W'" nrs="'0.29 / W'"
sa=0 sb=0 sd=0
model=nfet_g5v0d10v5
spiceprefix=X
}
C {devices/lab_wire.sym} 210 -290 0 0 {name=p5 sig_type=std_logic lab=nb1}
C {devices/lab_wire.sym} 370 -290 0 0 {name=p6 sig_type=std_logic lab=pb1}
C {devices/ipin.sym} 60 -290 0 0 {name=p7 lab=din1}
C {sky130_fd_pr/pfet_g5v0d10v5.sym} 530 -700 0 0 {name=M41
L=10
W=0.5
nf=1
mult=1
ad="'int((nf+1)/2) * W/nf * 0.29'" 
pd="'2*int((nf+1)/2) * (W/nf + 0.29)'"
as="'int((nf+2)/2) * W/nf * 0.29'" 
ps="'2*int((nf+2)/2) * (W/nf + 0.29)'"
nrd="'0.29 / W'" nrs="'0.29 / W'"
sa=0 sb=0 sd=0
model=pfet_g5v0d10v5
spiceprefix=X
}
C {sky130_fd_pr/nfet_g5v0d10v5.sym} 530 -590 0 0 {name=M42
L=0.5
W=10
nf=1
mult=1
ad="'int((nf+1)/2) * W/nf * 0.29'" 
pd="'2*int((nf+1)/2) * (W/nf + 0.29)'"
as="'int((nf+2)/2) * W/nf * 0.29'" 
ps="'2*int((nf+2)/2) * (W/nf + 0.29)'"
nrd="'0.29 / W'" nrs="'0.29 / W'"
sa=0 sb=0 sd=0
model=nfet_g5v0d10v5
spiceprefix=X
}
C {sky130_fd_pr/pfet_g5v0d10v5.sym} 680 -700 0 0 {name=M43
L=10
W=0.5
nf=1
mult=1
ad="'int((nf+1)/2) * W/nf * 0.29'" 
pd="'2*int((nf+1)/2) * (W/nf + 0.29)'"
as="'int((nf+2)/2) * W/nf * 0.29'" 
ps="'2*int((nf+2)/2) * (W/nf + 0.29)'"
nrd="'0.29 / W'" nrs="'0.29 / W'"
sa=0 sb=0 sd=0
model=pfet_g5v0d10v5
spiceprefix=X
}
C {sky130_fd_pr/nfet_g5v0d10v5.sym} 680 -590 0 0 {name=M44
L=0.5
W=10
nf=1
mult=1
ad="'int((nf+1)/2) * W/nf * 0.29'" 
pd="'2*int((nf+1)/2) * (W/nf + 0.29)'"
as="'int((nf+2)/2) * W/nf * 0.29'" 
ps="'2*int((nf+2)/2) * (W/nf + 0.29)'"
nrd="'0.29 / W'" nrs="'0.29 / W'"
sa=0 sb=0 sd=0
model=nfet_g5v0d10v5
spiceprefix=X
}
C {devices/lab_wire.sym} 620 -630 0 0 {name=p8 sig_type=std_logic lab=nb2}
C {devices/lab_wire.sym} 780 -630 0 0 {name=p9 sig_type=std_logic lab=pb2}
C {devices/ipin.sym} 470 -630 0 0 {name=p10 lab=din2}
C {sky130_fd_pr/pfet_g5v0d10v5.sym} 530 -360 0 0 {name=M45
L=10
W=0.5
nf=1
mult=1
ad="'int((nf+1)/2) * W/nf * 0.29'" 
pd="'2*int((nf+1)/2) * (W/nf + 0.29)'"
as="'int((nf+2)/2) * W/nf * 0.29'" 
ps="'2*int((nf+2)/2) * (W/nf + 0.29)'"
nrd="'0.29 / W'" nrs="'0.29 / W'"
sa=0 sb=0 sd=0
model=pfet_g5v0d10v5
spiceprefix=X
}
C {sky130_fd_pr/nfet_g5v0d10v5.sym} 530 -250 0 0 {name=M46
L=0.5
W=10
nf=1
mult=1
ad="'int((nf+1)/2) * W/nf * 0.29'" 
pd="'2*int((nf+1)/2) * (W/nf + 0.29)'"
as="'int((nf+2)/2) * W/nf * 0.29'" 
ps="'2*int((nf+2)/2) * (W/nf + 0.29)'"
nrd="'0.29 / W'" nrs="'0.29 / W'"
sa=0 sb=0 sd=0
model=nfet_g5v0d10v5
spiceprefix=X
}
C {sky130_fd_pr/pfet_g5v0d10v5.sym} 680 -360 0 0 {name=M47
L=10
W=0.5
nf=1
mult=1
ad="'int((nf+1)/2) * W/nf * 0.29'" 
pd="'2*int((nf+1)/2) * (W/nf + 0.29)'"
as="'int((nf+2)/2) * W/nf * 0.29'" 
ps="'2*int((nf+2)/2) * (W/nf + 0.29)'"
nrd="'0.29 / W'" nrs="'0.29 / W'"
sa=0 sb=0 sd=0
model=pfet_g5v0d10v5
spiceprefix=X
}
C {sky130_fd_pr/nfet_g5v0d10v5.sym} 680 -250 0 0 {name=M48
L=0.5
W=10
nf=1
mult=1
ad="'int((nf+1)/2) * W/nf * 0.29'" 
pd="'2*int((nf+1)/2) * (W/nf + 0.29)'"
as="'int((nf+2)/2) * W/nf * 0.29'" 
ps="'2*int((nf+2)/2) * (W/nf + 0.29)'"
nrd="'0.29 / W'" nrs="'0.29 / W'"
sa=0 sb=0 sd=0
model=nfet_g5v0d10v5
spiceprefix=X
}
C {devices/lab_wire.sym} 620 -290 0 0 {name=p11 sig_type=std_logic lab=nb3}
C {devices/lab_wire.sym} 780 -290 0 0 {name=p12 sig_type=std_logic lab=pb3}
C {devices/ipin.sym} 470 -290 0 0 {name=p13 lab=din3}
C {sky130_fd_pr/pfet_g5v0d10v5.sym} 930 -700 0 0 {name=M49
L=10
W=0.5
nf=1
mult=1
ad="'int((nf+1)/2) * W/nf * 0.29'" 
pd="'2*int((nf+1)/2) * (W/nf + 0.29)'"
as="'int((nf+2)/2) * W/nf * 0.29'" 
ps="'2*int((nf+2)/2) * (W/nf + 0.29)'"
nrd="'0.29 / W'" nrs="'0.29 / W'"
sa=0 sb=0 sd=0
model=pfet_g5v0d10v5
spiceprefix=X
}
C {sky130_fd_pr/nfet_g5v0d10v5.sym} 930 -590 0 0 {name=M50
L=0.5
W=10
nf=1
mult=1
ad="'int((nf+1)/2) * W/nf * 0.29'" 
pd="'2*int((nf+1)/2) * (W/nf + 0.29)'"
as="'int((nf+2)/2) * W/nf * 0.29'" 
ps="'2*int((nf+2)/2) * (W/nf + 0.29)'"
nrd="'0.29 / W'" nrs="'0.29 / W'"
sa=0 sb=0 sd=0
model=nfet_g5v0d10v5
spiceprefix=X
}
C {sky130_fd_pr/pfet_g5v0d10v5.sym} 1080 -700 0 0 {name=M51
L=10
W=0.5
nf=1
mult=1
ad="'int((nf+1)/2) * W/nf * 0.29'" 
pd="'2*int((nf+1)/2) * (W/nf + 0.29)'"
as="'int((nf+2)/2) * W/nf * 0.29'" 
ps="'2*int((nf+2)/2) * (W/nf + 0.29)'"
nrd="'0.29 / W'" nrs="'0.29 / W'"
sa=0 sb=0 sd=0
model=pfet_g5v0d10v5
spiceprefix=X
}
C {sky130_fd_pr/nfet_g5v0d10v5.sym} 1080 -590 0 0 {name=M52
L=0.5
W=10
nf=1
mult=1
ad="'int((nf+1)/2) * W/nf * 0.29'" 
pd="'2*int((nf+1)/2) * (W/nf + 0.29)'"
as="'int((nf+2)/2) * W/nf * 0.29'" 
ps="'2*int((nf+2)/2) * (W/nf + 0.29)'"
nrd="'0.29 / W'" nrs="'0.29 / W'"
sa=0 sb=0 sd=0
model=nfet_g5v0d10v5
spiceprefix=X
}
C {devices/lab_wire.sym} 1020 -630 0 0 {name=p14 sig_type=std_logic lab=nb4}
C {devices/lab_wire.sym} 1180 -630 0 0 {name=p15 sig_type=std_logic lab=pb4}
C {devices/ipin.sym} 870 -630 0 0 {name=p16 lab=din4}
C {sky130_fd_pr/pfet_g5v0d10v5.sym} 930 -360 0 0 {name=M53
L=10
W=0.5
nf=1
mult=1
ad="'int((nf+1)/2) * W/nf * 0.29'" 
pd="'2*int((nf+1)/2) * (W/nf + 0.29)'"
as="'int((nf+2)/2) * W/nf * 0.29'" 
ps="'2*int((nf+2)/2) * (W/nf + 0.29)'"
nrd="'0.29 / W'" nrs="'0.29 / W'"
sa=0 sb=0 sd=0
model=pfet_g5v0d10v5
spiceprefix=X
}
C {sky130_fd_pr/nfet_g5v0d10v5.sym} 930 -250 0 0 {name=M54
L=0.5
W=10
nf=1
mult=1
ad="'int((nf+1)/2) * W/nf * 0.29'" 
pd="'2*int((nf+1)/2) * (W/nf + 0.29)'"
as="'int((nf+2)/2) * W/nf * 0.29'" 
ps="'2*int((nf+2)/2) * (W/nf + 0.29)'"
nrd="'0.29 / W'" nrs="'0.29 / W'"
sa=0 sb=0 sd=0
model=nfet_g5v0d10v5
spiceprefix=X
}
C {sky130_fd_pr/pfet_g5v0d10v5.sym} 1080 -360 0 0 {name=M55
L=10
W=0.5
nf=1
mult=1
ad="'int((nf+1)/2) * W/nf * 0.29'" 
pd="'2*int((nf+1)/2) * (W/nf + 0.29)'"
as="'int((nf+2)/2) * W/nf * 0.29'" 
ps="'2*int((nf+2)/2) * (W/nf + 0.29)'"
nrd="'0.29 / W'" nrs="'0.29 / W'"
sa=0 sb=0 sd=0
model=pfet_g5v0d10v5
spiceprefix=X
}
C {sky130_fd_pr/nfet_g5v0d10v5.sym} 1080 -250 0 0 {name=M56
L=0.5
W=10
nf=1
mult=1
ad="'int((nf+1)/2) * W/nf * 0.29'" 
pd="'2*int((nf+1)/2) * (W/nf + 0.29)'"
as="'int((nf+2)/2) * W/nf * 0.29'" 
ps="'2*int((nf+2)/2) * (W/nf + 0.29)'"
nrd="'0.29 / W'" nrs="'0.29 / W'"
sa=0 sb=0 sd=0
model=nfet_g5v0d10v5
spiceprefix=X
}
C {devices/lab_wire.sym} 1020 -290 0 0 {name=p17 sig_type=std_logic lab=nb5}
C {devices/lab_wire.sym} 1180 -290 0 0 {name=p18 sig_type=std_logic lab=pb5}
C {devices/ipin.sym} 870 -290 0 0 {name=p19 lab=din5}
C {sky130_fd_pr/pfet_g5v0d10v5.sym} 1340 -700 0 0 {name=M57
L=10
W=0.5
nf=1
mult=1
ad="'int((nf+1)/2) * W/nf * 0.29'" 
pd="'2*int((nf+1)/2) * (W/nf + 0.29)'"
as="'int((nf+2)/2) * W/nf * 0.29'" 
ps="'2*int((nf+2)/2) * (W/nf + 0.29)'"
nrd="'0.29 / W'" nrs="'0.29 / W'"
sa=0 sb=0 sd=0
model=pfet_g5v0d10v5
spiceprefix=X
}
C {sky130_fd_pr/nfet_g5v0d10v5.sym} 1340 -590 0 0 {name=M58
L=0.5
W=10
nf=1
mult=1
ad="'int((nf+1)/2) * W/nf * 0.29'" 
pd="'2*int((nf+1)/2) * (W/nf + 0.29)'"
as="'int((nf+2)/2) * W/nf * 0.29'" 
ps="'2*int((nf+2)/2) * (W/nf + 0.29)'"
nrd="'0.29 / W'" nrs="'0.29 / W'"
sa=0 sb=0 sd=0
model=nfet_g5v0d10v5
spiceprefix=X
}
C {sky130_fd_pr/pfet_g5v0d10v5.sym} 1490 -700 0 0 {name=M59
L=10
W=0.5
nf=1
mult=1
ad="'int((nf+1)/2) * W/nf * 0.29'" 
pd="'2*int((nf+1)/2) * (W/nf + 0.29)'"
as="'int((nf+2)/2) * W/nf * 0.29'" 
ps="'2*int((nf+2)/2) * (W/nf + 0.29)'"
nrd="'0.29 / W'" nrs="'0.29 / W'"
sa=0 sb=0 sd=0
model=pfet_g5v0d10v5
spiceprefix=X
}
C {sky130_fd_pr/nfet_g5v0d10v5.sym} 1490 -590 0 0 {name=M60
L=0.5
W=10
nf=1
mult=1
ad="'int((nf+1)/2) * W/nf * 0.29'" 
pd="'2*int((nf+1)/2) * (W/nf + 0.29)'"
as="'int((nf+2)/2) * W/nf * 0.29'" 
ps="'2*int((nf+2)/2) * (W/nf + 0.29)'"
nrd="'0.29 / W'" nrs="'0.29 / W'"
sa=0 sb=0 sd=0
model=nfet_g5v0d10v5
spiceprefix=X
}
C {devices/lab_wire.sym} 1430 -630 0 0 {name=p20 sig_type=std_logic lab=nb6}
C {devices/lab_wire.sym} 1590 -630 0 0 {name=p21 sig_type=std_logic lab=pb6}
C {devices/ipin.sym} 1280 -630 0 0 {name=p22 lab=din6}
C {sky130_fd_pr/pfet_g5v0d10v5.sym} 1340 -360 0 0 {name=M61
L=10
W=0.5
nf=1
mult=1
ad="'int((nf+1)/2) * W/nf * 0.29'" 
pd="'2*int((nf+1)/2) * (W/nf + 0.29)'"
as="'int((nf+2)/2) * W/nf * 0.29'" 
ps="'2*int((nf+2)/2) * (W/nf + 0.29)'"
nrd="'0.29 / W'" nrs="'0.29 / W'"
sa=0 sb=0 sd=0
model=pfet_g5v0d10v5
spiceprefix=X
}
C {sky130_fd_pr/nfet_g5v0d10v5.sym} 1340 -250 0 0 {name=M62
L=0.5
W=10
nf=1
mult=1
ad="'int((nf+1)/2) * W/nf * 0.29'" 
pd="'2*int((nf+1)/2) * (W/nf + 0.29)'"
as="'int((nf+2)/2) * W/nf * 0.29'" 
ps="'2*int((nf+2)/2) * (W/nf + 0.29)'"
nrd="'0.29 / W'" nrs="'0.29 / W'"
sa=0 sb=0 sd=0
model=nfet_g5v0d10v5
spiceprefix=X
}
C {sky130_fd_pr/pfet_g5v0d10v5.sym} 1490 -360 0 0 {name=M63
L=10
W=0.5
nf=1
mult=1
ad="'int((nf+1)/2) * W/nf * 0.29'" 
pd="'2*int((nf+1)/2) * (W/nf + 0.29)'"
as="'int((nf+2)/2) * W/nf * 0.29'" 
ps="'2*int((nf+2)/2) * (W/nf + 0.29)'"
nrd="'0.29 / W'" nrs="'0.29 / W'"
sa=0 sb=0 sd=0
model=pfet_g5v0d10v5
spiceprefix=X
}
C {sky130_fd_pr/nfet_g5v0d10v5.sym} 1490 -250 0 0 {name=M64
L=0.5
W=10
nf=1
mult=1
ad="'int((nf+1)/2) * W/nf * 0.29'" 
pd="'2*int((nf+1)/2) * (W/nf + 0.29)'"
as="'int((nf+2)/2) * W/nf * 0.29'" 
ps="'2*int((nf+2)/2) * (W/nf + 0.29)'"
nrd="'0.29 / W'" nrs="'0.29 / W'"
sa=0 sb=0 sd=0
model=nfet_g5v0d10v5
spiceprefix=X
}
C {devices/lab_wire.sym} 1430 -290 0 0 {name=p23 sig_type=std_logic lab=nb7}
C {devices/lab_wire.sym} 1590 -290 0 0 {name=p24 sig_type=std_logic lab=pb7}
C {devices/ipin.sym} 1280 -290 0 0 {name=p25 lab=din7}
C {devices/lab_wire.sym} 100 -920 3 0 {name=p26 sig_type=std_logic lab=pb0}
C {devices/lab_wire.sym} 180 -920 3 0 {name=p27 sig_type=std_logic lab=pb1}
C {devices/lab_wire.sym} 260 -920 3 0 {name=p28 sig_type=std_logic lab=pb2}
C {devices/lab_wire.sym} 340 -920 3 0 {name=p29 sig_type=std_logic lab=pb3}
C {devices/lab_wire.sym} 420 -920 3 0 {name=p30 sig_type=std_logic lab=pb4}
C {devices/lab_wire.sym} 500 -920 3 0 {name=p31 sig_type=std_logic lab=pb5}
C {devices/lab_wire.sym} 580 -920 3 0 {name=p32 sig_type=std_logic lab=pb6}
C {devices/lab_wire.sym} 660 -920 3 0 {name=p33 sig_type=std_logic lab=pb7}
C {devices/lab_wire.sym} 100 -1350 1 0 {name=p34 sig_type=std_logic lab=pb0}
C {devices/lab_wire.sym} 180 -1350 1 0 {name=p35 sig_type=std_logic lab=pb1}
C {devices/lab_wire.sym} 260 -1350 1 0 {name=p36 sig_type=std_logic lab=pb2}
C {devices/lab_wire.sym} 340 -1350 1 0 {name=p37 sig_type=std_logic lab=pb3}
C {devices/lab_wire.sym} 420 -1350 1 0 {name=p38 sig_type=std_logic lab=pb4}
C {devices/lab_wire.sym} 500 -1350 1 0 {name=p39 sig_type=std_logic lab=pb5}
C {devices/lab_wire.sym} 580 -1350 1 0 {name=p40 sig_type=std_logic lab=pb6}
C {devices/lab_wire.sym} 660 -1350 1 0 {name=p41 sig_type=std_logic lab=pb7}
C {devices/lab_wire.sym} 800 -1350 1 0 {name=p42 sig_type=std_logic lab=nb0}
C {devices/lab_wire.sym} 880 -1350 1 0 {name=p43 sig_type=std_logic lab=nb1}
C {devices/lab_wire.sym} 960 -1350 1 0 {name=p44 sig_type=std_logic lab=nb2}
C {devices/lab_wire.sym} 1040 -1350 1 0 {name=p45 sig_type=std_logic lab=nb3}
C {devices/lab_wire.sym} 1120 -1350 1 0 {name=p46 sig_type=std_logic lab=nb4}
C {devices/lab_wire.sym} 1200 -1350 1 0 {name=p47 sig_type=std_logic lab=nb5}
C {devices/lab_wire.sym} 1280 -1350 1 0 {name=p48 sig_type=std_logic lab=nb6}
C {devices/lab_wire.sym} 1360 -1350 1 0 {name=p49 sig_type=std_logic lab=nb7}
C {devices/lab_wire.sym} 800 -920 3 0 {name=p50 sig_type=std_logic lab=nb0}
C {devices/lab_wire.sym} 880 -920 3 0 {name=p51 sig_type=std_logic lab=nb1}
C {devices/lab_wire.sym} 960 -920 3 0 {name=p52 sig_type=std_logic lab=nb2}
C {devices/lab_wire.sym} 1040 -920 3 0 {name=p53 sig_type=std_logic lab=nb3}
C {devices/lab_wire.sym} 1120 -920 3 0 {name=p54 sig_type=std_logic lab=nb4}
C {devices/lab_wire.sym} 1200 -920 3 0 {name=p55 sig_type=std_logic lab=nb5}
C {devices/lab_wire.sym} 1280 -920 3 0 {name=p56 sig_type=std_logic lab=nb6}
C {devices/lab_wire.sym} 1360 -920 3 0 {name=p57 sig_type=std_logic lab=nb7}
C {devices/iopin.sym} 730 -1400 3 0 {name=p58 lab=tap}
C {devices/iopin.sym} 1390 -1160 0 0 {name=p59 lab=b}
C {devices/iopin.sym} 70 -1160 0 1 {name=p60 lab=a}
C {devices/ipin.sym} 210 -770 1 0 {name=p61 lab=dvdd}
C {devices/ipin.sym} 140 -510 0 0 {name=p69 lab=dvss}
C {devices/lab_wire.sym} 180 -1020 1 0 {name=p1 sig_type=std_logic lab=avss}
C {devices/lab_wire.sym} 260 -1020 1 0 {name=p62 sig_type=std_logic lab=avss}
C {devices/lab_wire.sym} 340 -1020 1 0 {name=p63 sig_type=std_logic lab=avss}
C {devices/lab_wire.sym} 420 -1020 1 0 {name=p64 sig_type=std_logic lab=avss}
C {devices/lab_wire.sym} 500 -1020 1 0 {name=p65 sig_type=std_logic lab=avss}
C {devices/lab_wire.sym} 580 -1020 1 0 {name=p66 sig_type=std_logic lab=avss}
C {devices/lab_wire.sym} 660 -1020 1 0 {name=p67 sig_type=std_logic lab=avss}
C {devices/lab_wire.sym} 800 -1020 1 0 {name=p68 sig_type=std_logic lab=avss}
C {devices/lab_wire.sym} 880 -1020 1 0 {name=p70 sig_type=std_logic lab=avss}
C {devices/lab_wire.sym} 960 -1020 1 0 {name=p71 sig_type=std_logic lab=avss}
C {devices/lab_wire.sym} 1040 -1020 1 0 {name=p72 sig_type=std_logic lab=avss}
C {devices/lab_wire.sym} 1120 -1020 1 0 {name=p73 sig_type=std_logic lab=avss}
C {devices/lab_wire.sym} 1200 -1020 1 0 {name=p74 sig_type=std_logic lab=avss}
C {devices/lab_wire.sym} 1280 -1020 1 0 {name=p75 sig_type=std_logic lab=avss}
C {devices/lab_wire.sym} 1360 -1020 1 0 {name=p76 sig_type=std_logic lab=avss}
C {devices/lab_wire.sym} 180 -1220 3 0 {name=p77 sig_type=std_logic lab=avdd}
C {devices/lab_wire.sym} 260 -1220 3 0 {name=p78 sig_type=std_logic lab=avdd}
C {devices/lab_wire.sym} 340 -1220 3 0 {name=p79 sig_type=std_logic lab=avdd}
C {devices/lab_wire.sym} 420 -1220 3 0 {name=p80 sig_type=std_logic lab=avdd}
C {devices/lab_wire.sym} 500 -1220 3 0 {name=p81 sig_type=std_logic lab=avdd}
C {devices/lab_wire.sym} 580 -1220 3 0 {name=p82 sig_type=std_logic lab=avdd}
C {devices/lab_wire.sym} 660 -1220 3 0 {name=p83 sig_type=std_logic lab=avdd}
C {devices/lab_wire.sym} 800 -1220 3 0 {name=p84 sig_type=std_logic lab=avdd}
C {devices/lab_wire.sym} 880 -1220 3 0 {name=p85 sig_type=std_logic lab=avdd}
C {devices/lab_wire.sym} 960 -1220 3 0 {name=p86 sig_type=std_logic lab=avdd}
C {devices/lab_wire.sym} 1040 -1220 3 0 {name=p87 sig_type=std_logic lab=avdd}
C {devices/lab_wire.sym} 1120 -1220 3 0 {name=p88 sig_type=std_logic lab=avdd}
C {devices/lab_wire.sym} 1200 -1220 3 0 {name=p89 sig_type=std_logic lab=avdd}
C {devices/lab_wire.sym} 1280 -1220 3 0 {name=p90 sig_type=std_logic lab=avdd}
C {devices/lab_wire.sym} 1360 -1220 3 0 {name=p91 sig_type=std_logic lab=avdd}
C {devices/lab_wire.sym} 620 -770 1 0 {name=p92 sig_type=std_logic lab=dvdd}
C {devices/lab_wire.sym} 620 -510 3 0 {name=p93 sig_type=std_logic lab=dvss}
C {devices/lab_wire.sym} 1020 -770 1 0 {name=p94 sig_type=std_logic lab=dvdd}
C {devices/lab_wire.sym} 1020 -510 3 0 {name=p95 sig_type=std_logic lab=dvss}
C {devices/lab_wire.sym} 1440 -770 1 0 {name=p96 sig_type=std_logic lab=dvdd}
C {devices/lab_wire.sym} 1440 -510 3 0 {name=p97 sig_type=std_logic lab=dvss}
C {devices/lab_wire.sym} 220 -430 1 0 {name=p98 sig_type=std_logic lab=dvdd}
C {devices/lab_wire.sym} 220 -170 3 0 {name=p99 sig_type=std_logic lab=dvss}
C {devices/lab_wire.sym} 630 -430 1 0 {name=p100 sig_type=std_logic lab=dvdd}
C {devices/lab_wire.sym} 630 -170 3 0 {name=p101 sig_type=std_logic lab=dvss}
C {devices/lab_wire.sym} 1030 -430 1 0 {name=p102 sig_type=std_logic lab=dvdd}
C {devices/lab_wire.sym} 1030 -170 3 0 {name=p103 sig_type=std_logic lab=dvss}
C {devices/lab_wire.sym} 1450 -430 1 0 {name=p104 sig_type=std_logic lab=dvdd}
C {devices/lab_wire.sym} 1450 -170 3 0 {name=p105 sig_type=std_logic lab=dvss}
C {devices/ipin.sym} 100 -1010 1 0 {name=p106 lab=avss}
C {devices/ipin.sym} 100 -1230 3 0 {name=p107 lab=avdd}
